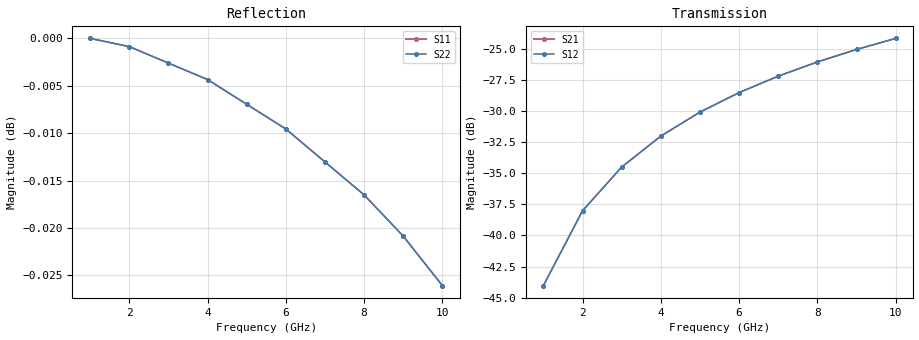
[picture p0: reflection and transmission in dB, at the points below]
! Created Mon Sep 20 20:53:08 2021
# hz S ma R 50
! 2 Port Network Data from SP1.SP block
! freq  magS11  angS11  magS21  angS21  magS12  angS12  magS22  angS22
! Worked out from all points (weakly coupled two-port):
!   10 points, 1 GHz to 10 GHz, reference 50 ohm
!   highest |S21| = -24.16 dB at 10 GHz (marker M1); lowest = -44.0 dB at 1 GHz (marker M2)
!   lowest |S11| = 0.0 dB at 10 GHz (marker M3), VSWR 676.66, Z = 6.2 - j455 ohm
!   |S11| at or under -10 dB: nowhere
!   |S22| runs from 0.0 to 0.0 dB; largest |S21 - S12| = 0
1e9  1 -1.3  0.006282 88.7  0.006282 88.7  1 -1.3
2e9  0.9999 -2.5  0.01256 87.4  0.01256 87.4  0.9999 -2.5
3e9  0.9997 -3.8  0.01883 86.1  0.01883 86.1  0.9997 -3.8
4e9  0.9995 -5.0  0.02508 84.8  0.02508 84.8  0.9995 -5.0
5e9  0.9992 -6.3  0.03131 83.5  0.03131 83.5  0.9992 -6.3
6e9  0.9989 -7.5  0.03751 82.2  0.03751 82.2  0.9989 -7.5
7e9  0.9985 -8.8  0.04368 80.9  0.04368 80.9  0.9985 -8.8
8e9  0.9981 -10.0  0.04982 79.6  0.04982 79.6  0.9981 -10.0
9e9  0.9976 -11.3  0.05591 78.3  0.05591 78.3  0.9976 -11.3
1e10  0.997 -12.5  0.06196 77.0  0.06196 77.0  0.997 -12.5
